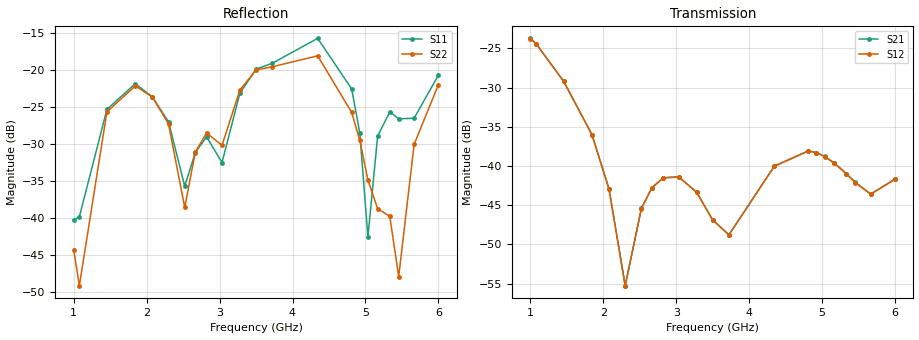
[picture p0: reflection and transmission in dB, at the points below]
!Agilent Technologies,E8364B,MY43040528,A.07.50.67
!Agilent E8364B: A.07.50.67
!Date: Sunday, March 01, 2026 21:20:29
!Correction: S11(Full 2 Port(1,2))
!S21(Full 2 Port(1,2))
!S12(Full 2 Port(1,2))
!S22(Full 2 Port(1,2))
!S2P File: Measurements: S11, S21, S12, S22:
# Hz S  dB  R 50
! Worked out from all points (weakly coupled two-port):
!   451 points, 1 GHz to 6 GHz, reference 50 ohm
!   highest |S21| = -23.74 dB at 1 GHz (marker M1); lowest = -55.3 dB at 2.3 GHz (marker M2)
!   lowest |S11| = -42.6 dB at 5.033 GHz (marker M3), VSWR 1.01, Z = 50.1 - j0.735 ohm
!   |S11| at or under -10 dB: start of sweep to end of sweep
!   |S22| runs from -50.1 to -17.2 dB; largest |S21 - S12| = 0.00025
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1e9  -40.32 83.6  -23.74 148.8  -23.77 148.8  -44.32 4.5
1.077778e9  -39.86 120.7  -24.40 103.7  -24.43 103.8  -49.21 65.3
1.455556e9  -25.31 155.7  -29.19 -111.0  -29.22 -111.0  -25.63 96.7
1.844444e9  -21.82 86.8  -36.00 38.5  -36.03 38.5  -22.12 1.3
2.077778e9  -23.60 57.2  -42.89 -84.5  -42.96 -84.4  -23.61 -42.9
2.3e9  -26.98 32.5  -55.25 -131.3  -55.23 -131.4  -27.27 -82.8
2.522222e9  -35.71 50.9  -45.40 172.1  -45.43 172.1  -38.59 -67.1
2.666667e9  -31.15 82.6  -42.75 96.7  -42.79 96.6  -31.11 -34.1
2.822222e9  -29.03 66.8  -41.50 12.8  -41.53 12.8  -28.48 -59.7
3.033333e9  -32.51 80.4  -41.37 -102.0  -41.39 -102.0  -30.19 -59.2
3.277778e9  -23.13 93.6  -43.32 128.0  -43.35 127.9  -22.68 -65.3
3.5e9  -19.84 60.8  -46.88 23.4  -46.89 23.5  -19.95 -107.0
3.722222e9  -19.05 38.8  -48.76 -52.3  -48.79 -52.1  -19.52 -138.7
4.344444e9  -15.67 -40.7  -40.01 14.0  -40.05 14.1  -18.04 104.3
4.811111e9  -22.53 -121.1  -38.06 107.8  -38.10 107.8  -25.72 -27.1
4.922222e9  -28.52 -137.9  -38.29 41.8  -38.32 41.9  -29.50 -72.8
5.033333e9  -42.62 -82.6  -38.77 -24.7  -38.81 -24.7  -34.88 -132.7
5.166667e9  -28.92 -33.5  -39.62 -105.6  -39.66 -105.6  -38.76 124.3
5.333333e9  -25.64 -58.8  -40.97 149.9  -41.02 149.9  -39.81 19.0
5.455556e9  -26.58 -70.3  -42.10 69.1  -42.13 69.1  -47.97 -105.9
5.666667e9  -26.50 -53.6  -43.57 -80.7  -43.60 -80.6  -30.05 93.6
6e9  -20.65 -74.5  -41.64 43.1  -41.68 43.1  -21.95 -7.9
